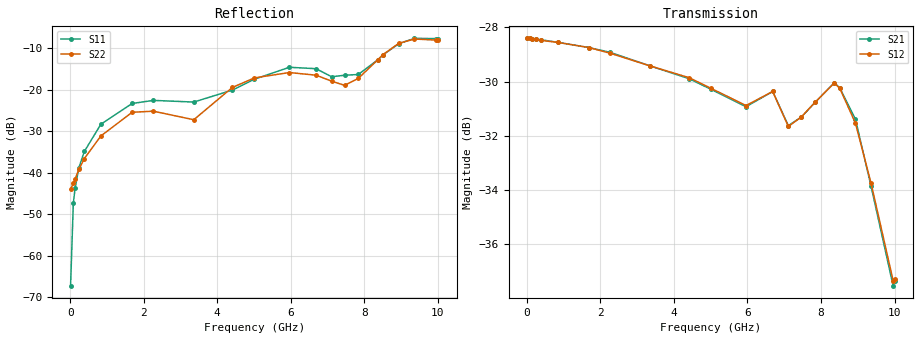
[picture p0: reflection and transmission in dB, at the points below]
! Device ID: PE43704
! Dir: z:\PE43704\PE43704_Char_1_20130516\PE43704\AMB\3p400V\27p50dB
! Serial: 14
! Insertion: A
! Impedance: 50 ohm
! Temp: Amb
! VDD: 3.400V
! Attenuation Step: 27.50dB
! IDD: 1.140536e-01mA
#  Hz  S  RI  R  50
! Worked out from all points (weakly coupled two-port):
!   401 points, 10 MHz to 10.01 GHz, reference 50 ohm
!   highest |S21| = -28.40 dB at 10 MHz (marker M1); lowest = -37.5 dB at 9.96 GHz (marker M2)
!   lowest |S11| = -67.2 dB at 10 MHz (marker M3), VSWR 1.00, Z = 50 + j0.0427 ohm
!   |S11| at or under -10 dB: start of sweep to 8.737 GHz
!   |S22| runs from -44.0 to -7.8 dB; largest |S21 - S12| = 0.00072
!   S11 on the Smith chart (normalised r, x): 10 MHz: 1.00, +0.00; 7.46 GHz: 0.78, +0.14; 8.51 GHz: 0.80, +0.45; 9.36 GHz: 0.54, +0.48; 10.01 GHz: 0.46, +0.27
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1e7  -8.49e-05 0.000427  0.038 -0.000136  0.038 -0.000121  0.0063 0.000393
8.5e7  1.71e-05 0.00431  0.038 -0.000833  0.038 -0.000837  0.00648 0.00367
1.35e8  -0.000165 0.00657  0.0379 -0.00132  0.0379 -0.0013  0.0062 0.00571
2.35e8  -0.00186 0.0113  0.0378 -0.00227  0.0378 -0.00226  0.00477 0.00982
3.85e8  -0.00496 0.0173  0.0376 -0.00376  0.0375 -0.00369  0.00161 0.0147
8.35e8  -0.0251 0.0289  0.0366 -0.00758  0.0366 -0.00756  -0.0165 0.0222
1.685e9  -0.0663 0.015  0.0336 -0.0144  0.0336 -0.0144  -0.0532 0.00236
2.26e9  -0.074 -0.00215  0.0308 -0.0183  0.0307 -0.0182  -0.0534 -0.0128
3.36e9  -0.0707 -0.000885  0.0239 -0.0239  0.0239 -0.0239  -0.043 0.00513
4.41e9  -0.0883 0.0435  0.0177 -0.0267  0.0178 -0.0268  -0.0925 0.0518
5.01e9  -0.1121 0.0718  0.0146 -0.0269  0.0147 -0.027  -0.1258 0.057
5.96e9  -0.1595 0.0945  0.00923 -0.0269  0.00937 -0.027  -0.1508 0.0543
6.685e9  -0.1594 0.0799  0.00665 -0.0296  0.00665 -0.0296  -0.1391 0.0531
7.11e9  -0.1288 0.0609  0.00159 -0.0262  0.00168 -0.0261  -0.1062 0.0681
7.46e9  -0.1186 0.0896  0.00237 -0.0271  0.00247 -0.0271  -0.0762 0.0827
7.835e9  -0.0727 0.1333  0.00179 -0.0289  0.00187 -0.0289  -0.0592 0.1228
8.36e9  -0.0408 0.2235  -0.00598 -0.0309  -0.00589 -0.0309  -0.0733 0.2148
8.51e9  -0.0443 0.2582  -0.00855 -0.0296  -0.0083 -0.0296  -0.0856 0.2495
8.935e9  -0.0966 0.3428  -0.0136 -0.0233  -0.0134 -0.0229  -0.1519 0.3266
9.36e9  -0.1875 0.3682  -0.0121 -0.0163  -0.0124 -0.0164  -0.2375 0.3289
9.96e9  -0.3164 0.2612  -0.00363 -0.0128  -0.00365 -0.0131  -0.3487 0.1835
1.001e10  -0.3248 0.2417  -0.00275 -0.0133  -0.00235 -0.0135  -0.3534 0.1639
